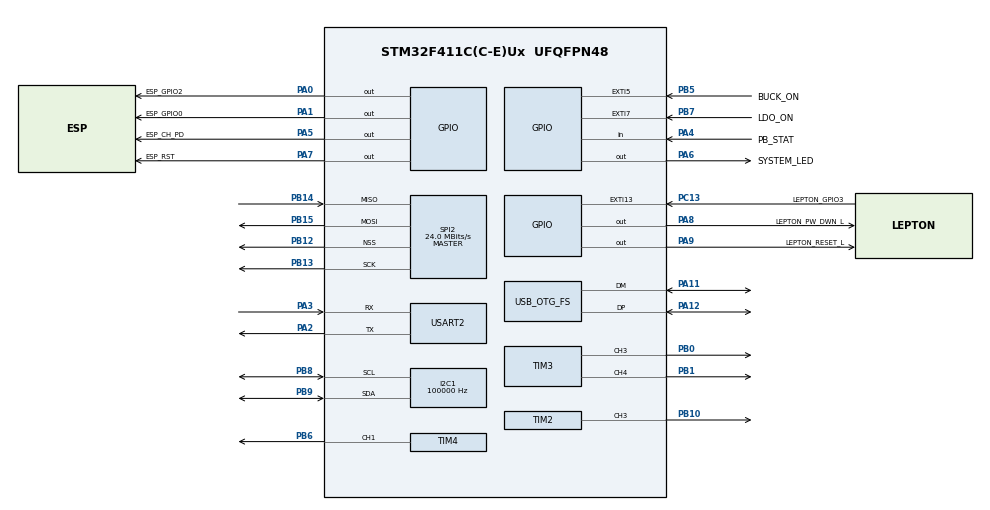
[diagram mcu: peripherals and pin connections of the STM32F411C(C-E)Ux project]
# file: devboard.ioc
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Dma.MEMTOMEM.0.Direction=DMA_MEMORY_TO_MEMORY
Dma.MEMTOMEM.0.FIFOMode=DMA_FIFOMODE_ENABLE
Dma.MEMTOMEM.0.FIFOThreshold=DMA_FIFO_THRESHOLD_FULL
Dma.MEMTOMEM.0.Instance=DMA2_Stream0
Dma.MEMTOMEM.0.MemBurst=DMA_MBURST_SINGLE
Dma.MEMTOMEM.0.MemDataAlignment=DMA_MDATAALIGN_HALFWORD
Dma.MEMTOMEM.0.MemInc=DMA_MINC_ENABLE
Dma.MEMTOMEM.0.Mode=DMA_NORMAL
Dma.MEMTOMEM.0.PeriphBurst=DMA_PBURST_SINGLE
Dma.MEMTOMEM.0.PeriphDataAlignment=DMA_PDATAALIGN_HALFWORD
Dma.MEMTOMEM.0.PeriphInc=DMA_PINC_ENABLE
Dma.MEMTOMEM.0.Priority=DMA_PRIORITY_MEDIUM
Dma.Request0=MEMTOMEM
Dma.Request1=SPI2_RX
Dma.Request2=SPI2_TX
Dma.SPI2_RX.1.Direction=DMA_PERIPH_TO_MEMORY
Dma.SPI2_RX.1.FIFOMode=DMA_FIFOMODE_DISABLE
Dma.SPI2_RX.1.Instance=DMA1_Stream3
Dma.SPI2_RX.1.MemDataAlignment=DMA_MDATAALIGN_HALFWORD
Dma.SPI2_RX.1.MemInc=DMA_MINC_ENABLE
Dma.SPI2_RX.1.Mode=DMA_NORMAL
Dma.SPI2_RX.1.PeriphDataAlignment=DMA_PDATAALIGN_HALFWORD
Dma.SPI2_RX.1.PeriphInc=DMA_PINC_DISABLE
Dma.SPI2_RX.1.Priority=DMA_PRIORITY_VERY_HIGH
Dma.SPI2_TX.2.Direction=DMA_MEMORY_TO_PERIPH
Dma.SPI2_TX.2.FIFOMode=DMA_FIFOMODE_DISABLE
Dma.SPI2_TX.2.Instance=DMA1_Stream4
Dma.SPI2_TX.2.MemDataAlignment=DMA_MDATAALIGN_HALFWORD
Dma.SPI2_TX.2.MemInc=DMA_MINC_ENABLE
Dma.SPI2_TX.2.Mode=DMA_NORMAL
Dma.SPI2_TX.2.PeriphDataAlignment=DMA_PDATAALIGN_HALFWORD
Dma.SPI2_TX.2.PeriphInc=DMA_PINC_DISABLE
Dma.SPI2_TX.2.Priority=DMA_PRIORITY_VERY_HIGH
I2C1.ClockSpeed=100000
I2C1.I2C_Mode=I2C_Fast
Mcu.Family=STM32F4
Mcu.Name=STM32F411C(C-E)Ux
Mcu.Package=UFQFPN48
NVIC.DMA1_Stream3_IRQn=true\:0\:0\:false\:false\:true
NVIC.DMA1_Stream4_IRQn=true\:0\:0\:false\:false\:true
NVIC.DMA2_Stream0_IRQn=true\:0\:0\:false\:false\:true
NVIC.EXTI15_10_IRQn=true\:0\:0\:false\:false\:true
NVIC.OTG_FS_IRQn=true\:0\:0\:false\:false\:true
NVIC.PriorityGroup=NVIC_PRIORITYGROUP_4
PA0-WKUP.GPIO_Label=ESP_GPIO2
PA0-WKUP.GPIO_ModeDefaultOutputPP=GPIO_MODE_OUTPUT_PP
PA0-WKUP.GPIO_PuPd=GPIO_NOPULL
PA0-WKUP.GPIO_Speed=GPIO_SPEED_FREQ_LOW
PA0-WKUP.Signal=GPIO_Output
PA1.GPIO_Label=ESP_GPIO0
PA1.GPIO_ModeDefaultOutputPP=GPIO_MODE_OUTPUT_PP
PA1.GPIO_PuPd=GPIO_NOPULL
PA1.GPIO_Speed=GPIO_SPEED_FREQ_LOW
PA1.Signal=GPIO_Output
PA10.Signal=USB_OTG_FS_ID
PA11.Mode=Device_Only
PA11.Signal=USB_OTG_FS_DM
PA12.Mode=Device_Only
PA12.Signal=USB_OTG_FS_DP
PA13.Mode=JTAG_5_pins
PA13.Signal=SYS_JTMS-SWDIO
PA14.Mode=JTAG_5_pins
PA14.Signal=SYS_JTCK-SWCLK
PA15.Mode=JTAG_5_pins
PA15.Signal=SYS_JTDI
PA2.Mode=Asynchronous
PA2.Signal=USART2_TX
PA3.Mode=Asynchronous
PA3.Signal=USART2_RX
PA4.GPIO_Label=PB_STAT
PA4.GPIO_Mode=GPIO_MODE_INPUT
PA4.GPIO_PuPd=GPIO_NOPULL
PA4.Signal=GPIO_Input
PA5.GPIO_Label=ESP_CH_PD
PA5.GPIO_ModeDefaultOutputPP=GPIO_MODE_OUTPUT_PP
PA5.GPIO_PuPd=GPIO_NOPULL
PA5.GPIO_Speed=GPIO_SPEED_FREQ_LOW
PA5.Signal=GPIO_Output
PA6.GPIO_Label=SYSTEM_LED
PA6.GPIO_ModeDefaultOutputPP=GPIO_MODE_OUTPUT_PP
PA6.GPIO_PuPd=GPIO_NOPULL
PA6.GPIO_Speed=GPIO_SPEED_FREQ_LOW
PA6.Signal=GPIO_Output
PA7.GPIO_Label=ESP_RST
PA7.GPIO_ModeDefaultOutputPP=GPIO_MODE_OUTPUT_PP
PA7.GPIO_PuPd=GPIO_NOPULL
PA7.GPIO_Speed=GPIO_SPEED_FREQ_LOW
PA7.Signal=GPIO_Output
PA8.GPIO_Label=LEPTON_PW_DWN_L
PA8.GPIO_ModeDefaultOutputPP=GPIO_MODE_OUTPUT_PP
PA8.GPIO_PuPd=GPIO_NOPULL
PA8.GPIO_Speed=GPIO_SPEED_FREQ_LOW
PA8.Signal=GPIO_Output
PA9.GPIO_Label=LEPTON_RESET_L
PA9.GPIO_ModeDefaultOutputPP=GPIO_MODE_OUTPUT_PP
PA9.GPIO_PuPd=GPIO_NOPULL
PA9.GPIO_Speed=GPIO_SPEED_FREQ_LOW
PA9.Signal=GPIO_Output
PB0.Signal=S_TIM3_CH3
PB1.Signal=S_TIM3_CH4
PB10.Signal=S_TIM2_CH3
PB12.Mode=NSS_Signal_Hard_Output
PB12.Signal=SPI2_NSS
PB13.GPIO_Mode=GPIO_MODE_AF_PP
PB13.GPIO_PuPd=GPIO_NOPULL
PB13.GPIO_Speed=GPIO_SPEED_FREQ_VERY_HIGH
PB13.Mode=Full_Duplex_Master
PB13.Signal=SPI2_SCK
PB14.GPIO_Mode=GPIO_MODE_AF_PP
PB14.GPIO_PuPd=GPIO_NOPULL
PB14.GPIO_Speed=GPIO_SPEED_FREQ_VERY_HIGH
PB14.Mode=Full_Duplex_Master
PB14.Signal=SPI2_MISO
PB15.GPIO_Mode=GPIO_MODE_AF_PP
PB15.GPIO_PuPd=GPIO_NOPULL
PB15.GPIO_Speed=GPIO_SPEED_FREQ_VERY_HIGH
PB15.Mode=Full_Duplex_Master
PB15.Signal=SPI2_MOSI
PB3.Mode=JTAG_5_pins
PB3.Signal=SYS_JTDO-SWO
PB4.Mode=JTAG_5_pins
PB4.Signal=SYS_JTRST
PB5.GPIO_Label=BUCK_ON
PB5.GPIO_ModeDefaultEXTI=GPIO_MODE_EVT_RISING
PB5.GPIO_PuPd=GPIO_NOPULL
PB5.Signal=GPXTI5
PB6.Signal=S_TIM4_CH1
PB7.GPIO_Label=LDO_ON
PB7.GPIO_ModeDefaultEXTI=GPIO_MODE_EVT_RISING
PB7.GPIO_PuPd=GPIO_NOPULL
PB7.Signal=GPXTI7
PB8.Mode=I2C
PB8.Signal=I2C1_SCL
PB9.Mode=I2C
PB9.Signal=I2C1_SDA
PC13-ANTI_TAMP.GPIO_Label=LEPTON_GPIO3
PC13-ANTI_TAMP.GPIO_ModeDefaultEXTI=GPIO_MODE_IT_RISING
PC13-ANTI_TAMP.GPIO_PuPd=GPIO_NOPULL
PC13-ANTI_TAMP.Signal=GPXTI13
PH0\ -\ OSC_IN.Mode=HSE-External-Oscillator
PH0\ -\ OSC_IN.Signal=RCC_OSC_IN
PH1\ -\ OSC_OUT.Mode=HSE-External-Oscillator
PH1\ -\ OSC_OUT.Signal=RCC_OSC_OUT
ProjectManager.HeapSize=0x200
ProjectManager.StackSize=0x400
ProjectManager.TargetToolchain=SW4STM32
RCC.48MHZClocksFreq_Value=48000000
RCC.AHBFreq_Value=96000000
RCC.APB1CLKDivider=RCC_HCLK_DIV2
RCC.APB1Freq_Value=48000000
RCC.APB1TimFreq_Value=96000000
RCC.APB2Freq_Value=96000000
RCC.APB2TimFreq_Value=96000000
RCC.CortexFreq_Value=96000000
RCC.EnbaleCSS=true
RCC.HCLKFreq_Value=96000000
RCC.HSE_VALUE=12000000
RCC.HSI_VALUE=16000000
RCC.LSE_VALUE=32768
RCC.PLLM=8
RCC.PLLN=128
RCC.SYSCLKFreq_VALUE=96000000
RCC.SYSCLKSource=RCC_SYSCLKSOURCE_PLLCLK
RCC.VCOOutputFreq_Value=192000000
RCC.VDD_VALUE=2.8
SH.S_TIM2_CH3.0=TIM2_CH3,Output Compare3 CH3
SH.S_TIM3_CH3.0=TIM3_CH3,Output Compare3 CH3
SH.S_TIM3_CH4.0=TIM3_CH4,Output Compare4 CH4
SH.S_TIM4_CH1.0=TIM4_CH1,Output Compare1 CH1
SPI2.CLKPhase=SPI_PHASE_2EDGE
SPI2.CLKPolarity=SPI_POLARITY_HIGH
SPI2.CalculateBaudRate=24.0 MBits/s
SPI2.DataSize=SPI_DATASIZE_16BIT
SPI2.Mode=SPI_MODE_MASTER
SPI2.VirtualNSS=VM_NSSHARD
TIM2.Channel-Output\ Compare3\ CH3=TIM_CHANNEL_3
TIM3.Channel-Output\ Compare3\ CH3=TIM_CHANNEL_3
TIM3.Channel-Output\ Compare4\ CH4=TIM_CHANNEL_4
USB_DEVICE.CLASS_NAME_FS=CDC
USB_DEVICE.CONFIGURATION_STRING_CDC_FS=Video Streaming Configuration
USB_DEVICE.INTERFACE_STRING_CDC_FS=Video Streaming Interface
USB_DEVICE.MANUFACTURER_STRING=GroupGets
USB_DEVICE.PID_CDC_FS=0x0100
USB_DEVICE.PRODUCT_STRING_CDC_FS=PureThermal 1
USB_DEVICE.SERIALNUMBER_STRING_CDC_FS=v1.0.0
USB_DEVICE.USBD_DEBUG_LEVEL=2
USB_DEVICE.USBD_HandleTypeDef=hUsbDeviceFS
USB_DEVICE.USBD_SELF_POWERED=0
USB_DEVICE.VID=0x1e4e
USB_DEVICE.VirtualMode=Cdc
USB_DEVICE.VirtualModeFS=Cdc_FS
USB_OTG_FS.VirtualMode=Device_Only
USB_OTG_FS.vbus_sensing_enable=DISABLE
VP_CRC_VS_CRC.Mode=CRC_Activate
VP_USB_DEVICE_VS_USB_DEVICE_CDC_FS.Mode=CDC_FS
board=devboard

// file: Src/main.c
/**
  ******************************************************************************
  * File Name          : main.c
  * Description        : Main program body
  ******************************************************************************
  *
  * COPYRIGHT(c) 2017 STMicroelectronics
  *
  * Redistribution and use in source and binary forms, with or without modification,
  * are permitted provided that the following conditions are met:
  *   1. Redistributions of source code must retain the above copyright notice,
  *      this list of conditions and the following disclaimer.
  *   2. Redistributions in binary form must reproduce the above copyright notice,
  *      this list of conditions and the following disclaimer in the documentation
  *      and/or other materials provided with the distribution.
  *   3. Neither the name of STMicroelectronics nor the names of its contributors
  *      may be used to endorse or promote products derived from this software
  *      without specific prior written permission.
  *
  * THIS SOFTWARE IS PROVIDED BY THE COPYRIGHT HOLDERS AND CONTRIBUTORS "AS IS"
  * AND ANY EXPRESS OR IMPLIED WARRANTIES, INCLUDING, BUT NOT LIMITED TO, THE
  * IMPLIED WARRANTIES OF MERCHANTABILITY AND FITNESS FOR A PARTICULAR PURPOSE ARE
  * DISCLAIMED. IN NO EVENT SHALL THE COPYRIGHT HOLDER OR CONTRIBUTORS BE LIABLE
  * FOR ANY DIRECT, INDIRECT, INCIDENTAL, SPECIAL, EXEMPLARY, OR CONSEQUENTIAL
  * DAMAGES (INCLUDING, BUT NOT LIMITED TO, PROCUREMENT OF SUBSTITUTE GOODS OR
  * SERVICES; LOSS OF USE, DATA, OR PROFITS; OR BUSINESS INTERRUPTION) HOWEVER
  * CAUSED AND ON ANY THEORY OF LIABILITY, WHETHER IN CONTRACT, STRICT LIABILITY,
  * OR TORT (INCLUDING NEGLIGENCE OR OTHERWISE) ARISING IN ANY WAY OUT OF THE USE
  * OF THIS SOFTWARE, EVEN IF ADVISED OF THE POSSIBILITY OF SUCH DAMAGE.
  *
  ******************************************************************************
  */
#include "stm32f4xx_hal.h"
#include "usb_device.h"

/* USER CODE BEGIN Includes */

#include <stdint.h>
#include "pt.h"
#include "lepton.h"
#include "lepton_i2c.h"
#include "tmp007_i2c.h"
#include "usbd_uvc.h"
#include "usbd_uvc_if.h"
DMA_HandleTypeDef hdma_memtomem_dma2_stream0;

#include "tasks.h"
#include "project_config.h"

/* USER CODE END Includes */

CRC_HandleTypeDef hcrc;

I2C_HandleTypeDef hi2c1;

SPI_HandleTypeDef hspi2;
DMA_HandleTypeDef hdma_spi2_rx;
DMA_HandleTypeDef hdma_spi2_tx;

TIM_HandleTypeDef htim2;
TIM_HandleTypeDef htim3;
TIM_HandleTypeDef htim4;

UART_HandleTypeDef huart2;

/* USER CODE BEGIN PV */
/* Private variables ---------------------------------------------------------*/

#if defined(USART_DEBUG) || defined(GDB_SEMIHOSTING)
#define DEBUG_PRINTF(...) printf( __VA_ARGS__);
#else
#define DEBUG_PRINTF(...)
#endif

static struct pt lepton_task_pt;
static struct pt usb_task_pt;
static struct pt uart_task_pt;
static struct pt button_task_pt;

/* USER CODE END PV */

void SystemClock_Config(void);
void Error_Handler(void);
static void MX_GPIO_Init(void);
static void MX_DMA_Init(void);
static void MX_CRC_Init(void);
static void MX_I2C1_Init(void);
static void MX_SPI2_Init(void);
static void MX_TIM2_Init(void);
static void MX_TIM3_Init(void);
static void MX_TIM4_Init(void);
static void MX_USART2_UART_Init(void);

void HAL_TIM_MspPostInit(TIM_HandleTypeDef *htim);

/* USER CODE BEGIN PFP */
/* Private function prototypes -----------------------------------------------*/

/* USER CODE END PFP */

/* USER CODE BEGIN 0 */

#if defined(GDB_SEMIHOSTING)
extern void initialise_monitor_handles(void);
#endif

/* USER CODE END 0 */

int main(void)
{

  /* MCU Configuration----------------------------------------------------------*/

  /* Reset of all peripherals, Initializes the Flash interface and the Systick. */
  HAL_Init();

  /* Configure the system clock */
  SystemClock_Config();

  /* Initialize all configured peripherals */
  MX_GPIO_Init();
  MX_DMA_Init();
  MX_CRC_Init();
  MX_I2C1_Init();
  MX_SPI2_Init();
  MX_TIM2_Init();
  MX_TIM3_Init();
  MX_TIM4_Init();
  MX_USART2_UART_Init();
  MX_USB_DEVICE_Init();

  /* USER CODE BEGIN 2 */
#if defined(GDB_SEMIHOSTING)
  initialise_monitor_handles();
#endif

  HAL_GPIO_WritePin(GPIOA, GPIO_PIN_8, GPIO_PIN_RESET);

  /*Fix RX and TX pin switch by setting the following pins */
  HAL_GPIO_WritePin(GPIOA, GPIO_PIN_5, GPIO_PIN_SET);
  HAL_GPIO_WritePin(GPIOA, GPIO_PIN_0, GPIO_PIN_SET);
  HAL_GPIO_WritePin(GPIOA, GPIO_PIN_1, GPIO_PIN_SET);
  HAL_GPIO_WritePin(GPIOA, GPIO_PIN_7, GPIO_PIN_SET);

  // reinitialize uart with speed from config
  huart2.Init.BaudRate = USART_DEBUG_SPEED;
  HAL_UART_Init(&huart2);

  DEBUG_PRINTF("Hello, Lepton!\n\r");
  fflush(stdout);

  lepton_init();

  HAL_Delay(1000);

  init_lepton_command_interface();

#if defined(TMP007)
  DEBUG_PRINTF("reading_tmp007_regs...\n\r");

  read_tmp007_regs();
#endif

  DEBUG_PRINTF("Initialized...\n\r");

  HAL_Delay(250);

  MX_USB_DEVICE_Init();

  PT_INIT(&lepton_task_pt);
  PT_INIT(&usb_task_pt);
  PT_INIT(&uart_task_pt);

  /* USER CODE END 2 */

  /* Infinite loop */
  while (1)
  {

  /* USER CODE BEGIN 3 */

	  PT_SCHEDULE(lepton_task(&lepton_task_pt));
#ifndef THERMAL_DATA_UART
	  PT_SCHEDULE(usb_task(&usb_task_pt));
#else
	  PT_SCHEDULE(uart_task(&uart_task_pt));
#endif
#ifndef PT1LITE
	  PT_SCHEDULE(button_task(&button_task_pt));
#endif

  }
  /* USER CODE END 3 */

}

/** System Clock Configuration
*/
void SystemClock_Config(void)
{

  RCC_OscInitTypeDef RCC_OscInitStruct;
  RCC_ClkInitTypeDef RCC_ClkInitStruct;

  __HAL_RCC_PWR_CLK_ENABLE();

  __HAL_PWR_VOLTAGESCALING_CONFIG(PWR_REGULATOR_VOLTAGE_SCALE1);

  RCC_OscInitStruct.OscillatorType = RCC_OSCILLATORTYPE_HSE;
  RCC_OscInitStruct.HSEState = RCC_HSE_ON;
  RCC_OscInitStruct.PLL.PLLState = RCC_PLL_ON;
  RCC_OscInitStruct.PLL.PLLSource = RCC_PLLSOURCE_HSE;
  RCC_OscInitStruct.PLL.PLLM = 4;
  RCC_OscInitStruct.PLL.PLLN = 72;
  RCC_OscInitStruct.PLL.PLLP = RCC_PLLP_DIV2;
  RCC_OscInitStruct.PLL.PLLQ = 3;
  if (HAL_RCC_OscConfig(&RCC_OscInitStruct) != HAL_OK)
  {
    Error_Handler();
  }

  RCC_ClkInitStruct.ClockType = RCC_CLOCKTYPE_HCLK|RCC_CLOCKTYPE_SYSCLK
                              |RCC_CLOCKTYPE_PCLK1|RCC_CLOCKTYPE_PCLK2;
  RCC_ClkInitStruct.SYSCLKSource = RCC_SYSCLKSOURCE_PLLCLK;
  RCC_ClkInitStruct.AHBCLKDivider = RCC_SYSCLK_DIV1;
  RCC_ClkInitStruct.APB1CLKDivider = RCC_HCLK_DIV2;
  RCC_ClkInitStruct.APB2CLKDivider = RCC_HCLK_DIV1;
  if (HAL_RCC_ClockConfig(&RCC_ClkInitStruct, FLASH_LATENCY_3) != HAL_OK)
  {
    Error_Handler();
  }

  HAL_RCC_EnableCSS();

  HAL_SYSTICK_Config(HAL_RCC_GetHCLKFreq()/1000);

  HAL_SYSTICK_CLKSourceConfig(SYSTICK_CLKSOURCE_HCLK);

  /* SysTick_IRQn interrupt configuration */
  HAL_NVIC_SetPriority(SysTick_IRQn, 0, 0);
}

/* CRC init function */
static void MX_CRC_Init(void)
{

  hcrc.Instance = CRC;
  if (HAL_CRC_Init(&hcrc) != HAL_OK)
  {
    Error_Handler();
  }

}

/* I2C1 init function */
static void MX_I2C1_Init(void)
{

  hi2c1.Instance = I2C1;
  hi2c1.Init.ClockSpeed = 100000;
  hi2c1.Init.DutyCycle = I2C_DUTYCYCLE_2;
  hi2c1.Init.OwnAddress1 = 0;
  hi2c1.Init.AddressingMode = I2C_ADDRESSINGMODE_7BIT;
  hi2c1.Init.DualAddressMode = I2C_DUALADDRESS_DISABLE;
  hi2c1.Init.OwnAddress2 = 0;
  hi2c1.Init.GeneralCallMode = I2C_GENERALCALL_DISABLE;
  hi2c1.Init.NoStretchMode = I2C_NOSTRETCH_DISABLE;
  if (HAL_I2C_Init(&hi2c1) != HAL_OK)
  {
    Error_Handler();
  }

}

/* SPI2 init function */
static void MX_SPI2_Init(void)
{

  hspi2.Instance = SPI2;
  hspi2.Init.Mode = SPI_MODE_MASTER;
  hspi2.Init.Direction = SPI_DIRECTION_2LINES;
  hspi2.Init.DataSize = SPI_DATASIZE_16BIT;
  hspi2.Init.CLKPolarity = SPI_POLARITY_HIGH;
  hspi2.Init.CLKPhase = SPI_PHASE_2EDGE;
  hspi2.Init.NSS = SPI_NSS_HARD_OUTPUT;
  hspi2.Init.BaudRatePrescaler = SPI_BAUDRATEPRESCALER_2;
  hspi2.Init.FirstBit = SPI_FIRSTBIT_MSB;
  hspi2.Init.TIMode = SPI_TIMODE_DISABLE;
  hspi2.Init.CRCCalculation = SPI_CRCCALCULATION_DISABLE;
  hspi2.Init.CRCPolynomial = 10;
  if (HAL_SPI_Init(&hspi2) != HAL_OK)
  {
    Error_Handler();
  }

}

/* TIM2 init function */
static void MX_TIM2_Init(void)
{

  TIM_MasterConfigTypeDef sMasterConfig;
  TIM_OC_InitTypeDef sConfigOC;

  htim2.Instance = TIM2;
  htim2.Init.Prescaler = 0;
  htim2.Init.CounterMode = TIM_COUNTERMODE_UP;
  htim2.Init.Period = 0;
  htim2.Init.ClockDivision = TIM_CLOCKDIVISION_DIV1;
  if (HAL_TIM_OC_Init(&htim2) != HAL_OK)
  {
    Error_Handler();
  }

  sMasterConfig.MasterOutputTrigger = TIM_TRGO_RESET;
  sMasterConfig.MasterSlaveMode = TIM_MASTERSLAVEMODE_DISABLE;
  if (HAL_TIMEx_MasterConfigSynchronization(&htim2, &sMasterConfig) != HAL_OK)
  {
    Error_Handler();
  }

  sConfigOC.OCMode = TIM_OCMODE_TIMING;
  sConfigOC.Pulse = 0;
  sConfigOC.OCPolarity = TIM_OCPOLARITY_HIGH;
  sConfigOC.OCFastMode = TIM_OCFAST_DISABLE;
  if (HAL_TIM_OC_ConfigChannel(&htim2, &sConfigOC, TIM_CHANNEL_3) != HAL_OK)
  {
    Error_Handler();
  }

  HAL_TIM_MspPostInit(&htim2);

}

/* TIM3 init function */
static void MX_TIM3_Init(void)
{

  TIM_MasterConfigTypeDef sMasterConfig;
  TIM_OC_InitTypeDef sConfigOC;

  htim3.Instance = TIM3;
  htim3.Init.Prescaler = 0;
  htim3.Init.CounterMode = TIM_COUNTERMODE_UP;
  htim3.Init.Period = 0;
  htim3.Init.ClockDivision = TIM_CLOCKDIVISION_DIV1;
  if (HAL_TIM_OC_Init(&htim3) != HAL_OK)
  {
    Error_Handler();
  }

  sMasterConfig.MasterOutputTrigger = TIM_TRGO_RESET;
  sMasterConfig.MasterSlaveMode = TIM_MASTERSLAVEMODE_DISABLE;
  if (HAL_TIMEx_MasterConfigSynchronization(&htim3, &sMasterConfig) != HAL_OK)
  {
    Error_Handler();
  }

  sConfigOC.OCMode = TIM_OCMODE_TIMING;
  sConfigOC.Pulse = 0;
  sConfigOC.OCPolarity = TIM_OCPOLARITY_HIGH;
  sConfigOC.OCFastMode = TIM_OCFAST_DISABLE;
  if (HAL_TIM_OC_ConfigChannel(&htim3, &sConfigOC, TIM_CHANNEL_3) != HAL_OK)
  {
    Error_Handler();
  }

  if (HAL_TIM_OC_ConfigChannel(&htim3, &sConfigOC, TIM_CHANNEL_4) != HAL_OK)
  {
    Error_Handler();
  }

  HAL_TIM_MspPostInit(&htim3);

}

/* TIM4 init function */
static void MX_TIM4_Init(void)
{

  TIM_MasterConfigTypeDef sMasterConfig;
  TIM_OC_InitTypeDef sConfigOC;

  htim4.Instance = TIM4;
  htim4.Init.Prescaler = 0;
  htim4.Init.CounterMode = TIM_COUNTERMODE_UP;
  htim4.Init.Period = 0;
  htim4.Init.ClockDivision = TIM_CLOCKDIVISION_DIV1;
  if (HAL_TIM_OC_Init(&htim4) != HAL_OK)
  {
    Error_Handler();
  }

  sMasterConfig.MasterOutputTrigger = TIM_TRGO_RESET;
  sMasterConfig.MasterSlaveMode = TIM_MASTERSLAVEMODE_DISABLE;
  if (HAL_TIMEx_MasterConfigSynchronization(&htim4, &sMasterConfig) != HAL_OK)
  {
    Error_Handler();
  }

  sConfigOC.OCMode = TIM_OCMODE_TIMING;
  sConfigOC.Pulse = 0;
  sConfigOC.OCPolarity = TIM_OCPOLARITY_HIGH;
  sConfigOC.OCFastMode = TIM_OCFAST_DISABLE;
  if (HAL_TIM_OC_ConfigChannel(&htim4, &sConfigOC, TIM_CHANNEL_1) != HAL_OK)
  {
    Error_Handler();
  }

  HAL_TIM_MspPostInit(&htim4);

}

/* USART2 init function */
static void MX_USART2_UART_Init(void)
{

  huart2.Instance = USART2;
  huart2.Init.BaudRate = 115200;
  huart2.Init.WordLength = UART_WORDLENGTH_8B;
  huart2.Init.StopBits = UART_STOPBITS_1;
  huart2.Init.Parity = UART_PARITY_NONE;
  huart2.Init.Mode = UART_MODE_TX_RX;
  huart2.Init.HwFlowCtl = UART_HWCONTROL_NONE;
  huart2.Init.OverSampling = UART_OVERSAMPLING_16;
  if (HAL_UART_Init(&huart2) != HAL_OK)
  {
    Error_Handler();
  }

}

static void MX_DMA_Init(void)
{
  /* DMA controller clock enable */
  __HAL_RCC_DMA2_CLK_ENABLE();
  __HAL_RCC_DMA1_CLK_ENABLE();

  /* Configure DMA request hdma_memtomem_dma2_stream0 on DMA2_Stream0 */
  hdma_memtomem_dma2_stream0.Instance = DMA2_Stream0;
  hdma_memtomem_dma2_stream0.Init.Channel = DMA_CHANNEL_0;
  hdma_memtomem_dma2_stream0.Init.Direction = DMA_MEMORY_TO_MEMORY;
  hdma_memtomem_dma2_stream0.Init.PeriphInc = DMA_PINC_ENABLE;
  hdma_memtomem_dma2_stream0.Init.MemInc = DMA_MINC_ENABLE;
  hdma_memtomem_dma2_stream0.Init.PeriphDataAlignment = DMA_PDATAALIGN_HALFWORD;
  hdma_memtomem_dma2_stream0.Init.MemDataAlignment = DMA_MDATAALIGN_HALFWORD;
  hdma_memtomem_dma2_stream0.Init.Mode = DMA_NORMAL;
  hdma_memtomem_dma2_stream0.Init.Priority = DMA_PRIORITY_MEDIUM;
  hdma_memtomem_dma2_stream0.Init.FIFOMode = DMA_FIFOMODE_ENABLE;
  hdma_memtomem_dma2_stream0.Init.FIFOThreshold = DMA_FIFO_THRESHOLD_FULL;
  hdma_memtomem_dma2_stream0.Init.MemBurst = DMA_MBURST_SINGLE;
  hdma_memtomem_dma2_stream0.Init.PeriphBurst = DMA_PBURST_SINGLE;
  if (HAL_DMA_Init(&hdma_memtomem_dma2_stream0) != HAL_OK)
  {
    Error_Handler();
  }

  /* DMA interrupt init */
  /* DMA1_Stream3_IRQn interrupt configuration */
  HAL_NVIC_SetPriority(DMA1_Stream3_IRQn, 2, 0);
  HAL_NVIC_EnableIRQ(DMA1_Stream3_IRQn);
  /* DMA1_Stream4_IRQn interrupt configuration */
  HAL_NVIC_SetPriority(DMA1_Stream4_IRQn, 2, 0);
  HAL_NVIC_EnableIRQ(DMA1_Stream4_IRQn);
  /* DMA2_Stream0_IRQn interrupt configuration */
  HAL_NVIC_SetPriority(DMA2_Stream0_IRQn, 2, 0);
  HAL_NVIC_EnableIRQ(DMA2_Stream0_IRQn);

}

/** Configure pins as
        * Analog
        * Input
        * Output
        * EVENT_OUT
        * EXTI
*/
static void MX_GPIO_Init(void)
{

  GPIO_InitTypeDef GPIO_InitStruct;

  /* GPIO Ports Clock Enable */
  __HAL_RCC_GPIOC_CLK_ENABLE();
  __HAL_RCC_GPIOH_CLK_ENABLE();
  __HAL_RCC_GPIOA_CLK_ENABLE();
  __HAL_RCC_GPIOB_CLK_ENABLE();

  /*Configure GPIO pin : LEPTON_GPIO3_Pin */
  GPIO_InitStruct.Pin = LEPTON_GPIO3_Pin;
  GPIO_InitStruct.Mode = GPIO_MODE_IT_RISING;
  GPIO_InitStruct.Pull = GPIO_NOPULL;
  HAL_GPIO_Init(LEPTON_GPIO3_GPIO_Port, &GPIO_InitStruct);

  /*Configure GPIO pins : ESP_GPIO2_Pin ESP_GPIO0_Pin ESP_CH_PD_Pin SYSTEM_LED_Pin
                           ESP_RST_Pin LEPTON_PW_DWN_L_Pin LEPTON_RESET_L_Pin */
  GPIO_InitStruct.Pin = ESP_GPIO2_Pin|ESP_GPIO0_Pin|ESP_CH_PD_Pin|SYSTEM_LED_Pin
                          |ESP_RST_Pin|LEPTON_PW_DWN_L_Pin|LEPTON_RESET_L_Pin;
  GPIO_InitStruct.Mode = GPIO_MODE_OUTPUT_PP;
  GPIO_InitStruct.Pull = GPIO_NOPULL;
  GPIO_InitStruct.Speed = GPIO_SPEED_FREQ_LOW;
  HAL_GPIO_Init(GPIOA, &GPIO_InitStruct);

  /*Configure GPIO pin : PB_STAT_Pin */
  GPIO_InitStruct.Pin = PB_STAT_Pin;
  GPIO_InitStruct.Mode = GPIO_MODE_INPUT;
  GPIO_InitStruct.Pull = GPIO_NOPULL;
  HAL_GPIO_Init(PB_STAT_GPIO_Port, &GPIO_InitStruct);

  /*Configure GPIO pins : BUCK_ON_Pin LDO_ON_Pin */
 // GPIO_InitStruct.Pin = BUCK_ON_Pin|LDO_ON_Pin;
 // GPIO_InitStruct.Mode = GPIO_MODE_OUTPUT_PP;
 // GPIO_InitStruct.Pull = GPIO_PULLUP;
 // HAL_GPIO_Init(GPIOB, &GPIO_InitStruct);

  //HAL_GPIO_WritePin(GPIOB, BUCK_ON_Pin, GPIO_PIN_SET);
  //HAL_GPIO_WritePin(GPIOB, LDO_ON_Pin, GPIO_PIN_SET);

  /*Configure GPIO pin Output Level */
  HAL_GPIO_WritePin(GPIOA, ESP_GPIO2_Pin|ESP_GPIO0_Pin|ESP_CH_PD_Pin|SYSTEM_LED_Pin
                          |ESP_RST_Pin|LEPTON_PW_DWN_L_Pin|LEPTON_RESET_L_Pin, GPIO_PIN_RESET);

  /* EXTI interrupt init*/
  HAL_NVIC_SetPriority(EXTI15_10_IRQn, 0, 0);
  HAL_NVIC_EnableIRQ(EXTI15_10_IRQn);

}

void Error_Handler(void)
{
  while(1)
  {
  }
}

/************************ (C) COPYRIGHT STMicroelectronics *****END OF FILE****/
